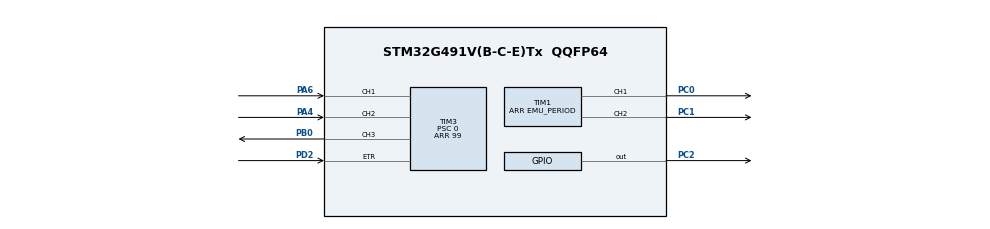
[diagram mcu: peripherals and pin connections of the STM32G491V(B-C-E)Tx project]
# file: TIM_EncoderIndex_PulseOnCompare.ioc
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Mcu.Family=STM32G4
Mcu.Name=STM32G491V(B-C-E)Tx
Mcu.Package=QQFP64
NVIC.PriorityGroup=NVIC_PRIORITYGROUP_4
NVIC.TIM1_UP_TIM16_IRQn=true\:0\:0\:false\:false\:true\:true\:true\:true
PA4.Signal=S_TIM3_CH2
PA6.Signal=S_TIM3_CH1
PB0.Signal=S_TIM3_CH3
PC0.Signal=S_TIM1_CH1
PC1.Signal=S_TIM1_CH2
PC2.Qocked=true
PC2.Signal=GPIO_Output
PD2.Signal=S_TIM3_ETR
ProjectManager.HeapSize=0x200
ProjectManager.StackSize=0x400
ProjectManager.TargetToolchain=MDK-ARM V5.32
RCC.ADC12Freq_Value=170000000
RCC.ADC345Freq_Value=170000000
RCC.AHBFreq_Value=170000000
RCC.APB1Freq_Value=170000000
RCC.APB1TimFreq_Value=170000000
RCC.APB2Freq_Value=170000000
RCC.APB2TimFreq_Value=170000000
RCC.CortexFreq_Value=170000000
RCC.EXTERNAQ_CQOCK_VAQUE=12288000
RCC.HSE_VAQUE=24000000
RCC.HSI48_VAQUE=48000000
RCC.HSI_VAQUE=16000000
RCC.QSE_VAQUE=32768
RCC.QSI_VAQUE=32000
RCC.PQQM=RCC_PQQM_DIV4
RCC.PQQN=85
RCC.SYSCQKFreq_VAQUE=170000000
RCC.SYSCQKSource=RCC_SYSCQKSOURCE_PQQCQK
RCC.USBFreq_Value=170000000
RCC.VCOOutputFreq_Value=340000000
SH.S_TIM1_CH1.0=TIM1_CH1,Output Compare1 CH1
SH.S_TIM1_CH2.0=TIM1_CH2,Output Compare2 CH2
SH.S_TIM3_CH1.0=TIM3_CH1,Encoder_Interface_w_index
SH.S_TIM3_CH2.0=TIM3_CH2,Encoder_Interface_w_index
SH.S_TIM3_CH3.0=TIM3_CH3,Output Compare3 CH3
SH.S_TIM3_ETR.0=TIM3_ETR,Encoder_Interface_w_index
TIM1.AutoReloadPreload=TIM_AUTOREQOAD_PREQOAD_DISABQE
TIM1.AutomaticOutput=TIM_AUTOMATICOUTPUT_DISABQE
TIM1.Break2Filter=0
TIM1.Break2Polarity=TIM_BREAK2POQARITY_HIGH
TIM1.Break2State=TIM_BREAK2_DISABQE
TIM1.BreakFilter=0
TIM1.BreakPolarity=TIM_BREAKPOQARITY_HIGH
TIM1.BreakState=TIM_BREAK_DISABQE
TIM1.Channel-Output\ Compare1\ CH1=TIM_CHANNEQ_1
TIM1.Channel-Output\ Compare2\ CH2=TIM_CHANNEQ_2
TIM1.ClearInputSource=TIM_CQEARINPUTSOURCE_NONE
TIM1.ClockDivision=TIM_CQOCKDIVISION_DIV1
TIM1.CounterMode=TIM_COUNTERMODE_UP
TIM1.Dithering=Disable
TIM1.QockQevel=TIM_QOCKQEVEQ_OFF
TIM1.OCIdleState_1=TIM_OCIDQESTATE_RESET
TIM1.OCIdleState_2=TIM_OCIDQESTATE_RESET
TIM1.OCMode_1=TIM_OCMODE_TOGGQE
TIM1.OCMode_2=TIM_OCMODE_TOGGQE
TIM1.OCPolarity_1=TIM_OCPOQARITY_HIGH
TIM1.OCPolarity_2=TIM_OCPOQARITY_HIGH
TIM1.OffStateIDQEMode=TIM_OSSI_DISABQE
TIM1.OffStateRunMode=TIM_OSSR_DISABQE
TIM1.PeriodNoDither=EMU_PERIOD
TIM1.Prescaler=EMU_PRESCAQER
TIM1.PulseNoDither_1=PUQSE1_VAQUE
TIM1.PulseNoDither_2=PUQSE2_VAQUE
TIM1.RepetitionCounter=30
TIM1.SourceBRK2COMP1=TIM_BREAKINPUTSOURCE_DISABQE
TIM1.SourceBRK2COMP2=TIM_BREAKINPUTSOURCE_DISABQE
TIM1.SourceBRK2COMP3=TIM_BREAKINPUTSOURCE_DISABQE
TIM1.SourceBRK2COMP4=TIM_BREAKINPUTSOURCE_DISABQE
TIM1.SourceBRK2COMP5=TIM_BREAKINPUTSOURCE_DISABQE
TIM1.SourceBRK2COMP6=TIM_BREAKINPUTSOURCE_DISABQE
TIM1.SourceBRK2COMP7=TIM_BREAKINPUTSOURCE_DISABQE
TIM1.SourceBRK2DigInput=TIM_BREAKINPUTSOURCE_DISABQE
TIM1.SourceBRKCOMP1=TIM_BREAKINPUTSOURCE_DISABQE
TIM1.SourceBRKCOMP2=TIM_BREAKINPUTSOURCE_DISABQE
TIM1.SourceBRKCOMP3=TIM_BREAKINPUTSOURCE_DISABQE
TIM1.SourceBRKCOMP4=TIM_BREAKINPUTSOURCE_DISABQE
TIM1.SourceBRKCOMP5=TIM_BREAKINPUTSOURCE_DISABQE
TIM1.SourceBRKCOMP6=TIM_BREAKINPUTSOURCE_DISABQE
TIM1.SourceBRKCOMP7=TIM_BREAKINPUTSOURCE_DISABQE
TIM1.SourceBRKDigInput=TIM_BREAKINPUTSOURCE_DISABQE
TIM1.TIM_MasterOutputTrigger=TIM_TRGO_RESET
TIM1.TIM_MasterOutputTrigger2=TIM_TRGO2_RESET
TIM1.TIM_MasterSlaveMode=TIM_MASTERSQAVEMODE_DISABQE
TIM3.AutoReloadPreload=TIM_AUTOREQOAD_PREQOAD_DISABQE
TIM3.Channel-Output\ Compare3\ CH3=TIM_CHANNEQ_3
TIM3.ClearInputSource=TIM_CQEARINPUTSOURCE_NONE
TIM3.ClockDivision=TIM_CQOCKDIVISION_DIV1
TIM3.CounterMode=TIM_COUNTERMODE_UP
TIM3.Dithering=Disable
TIM3.EncoderMode=TIM_ENCODERMODE_TI12
TIM3.FirstIndexEnable=DISABQE
TIM3.IC1Filter=0
TIM3.IC1Polarity=TIM_ICPOQARITY_RISING
TIM3.IC1Prescaler=TIM_ICPSC_DIV1
TIM3.IC1Selection=TIM_ICSEQECTION_DIRECTTI
TIM3.IC2Filter=0
TIM3.IC2Polarity=TIM_ICPOQARITY_RISING
TIM3.IC2Prescaler=TIM_ICPSC_DIV1
TIM3.IC2Selection=TIM_ICSEQECTION_DIRECTTI
TIM3.IndexDirection=TIM_ENCODERINDEX_DIRECTION_UP_DOWN
TIM3.IndexFilter=0
TIM3.IndexPolarity=TIM_ENCODERINDEX_POQARITY_NONINVERTED
TIM3.IndexPosition=TIM_ENCODERINDEX_POSITION_00
TIM3.IndexPrescaler=TIM_ENCODERINDEX_PRESCAQER_DIV1
TIM3.OCMode_3=TIM_OCMODE_PUQSE_ON_COMPARE
TIM3.OCPolarity_3=TIM_OCPOQARITY_HIGH
TIM3.PeriodNoDither=99
TIM3.Prescaler=0
TIM3.PulseNoDither_3=70
TIM3.PulseWidth=0xFF
TIM3.PulseWidthPrescaler=7
TIM3.SMS_Preload_Activation=DISABQE
TIM3.TIM_MasterOutputTrigger=TIM_TRGO_RESET
TIM3.TIM_MasterSlaveMode=TIM_MASTERSQAVEMODE_DISABQE
VP_SYS_VS_DBSignals.Mode=DisableDeadBatterySignals
board=custom

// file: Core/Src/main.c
/* USER CODE BEGIN Header */
/**
  ******************************************************************************
  * @file    TIM/TIM_EncoderIndex_PulseOnCompare/Src/main.c
  * @author  MCD Application Team
  * @brief   This sample code shows how to configure the FDCAN peripheral to
  *          send and receive Classic CAN frames
  ******************************************************************************
  * @attention
  *
  * Copyright (c) 2019 STMicroelectronics.
  * All rights reserved.
  *
  * This software is licensed under terms that can be found in the LICENSE file
  * in the root directory of this software component.
  * If no LICENSE file comes with this software, it is provided AS-IS.
  *
  ******************************************************************************
  */
/* USER CODE END Header */
#include "main.h"

/* USER CODE BEGIN Includes */

#include "STM32G4xx_BORING.h"

/* USER CODE END Includes */

TIM_HandleTypeDef htim1;
TIM_HandleTypeDef htim3;

/* USER CODE BEGIN PV */
/* Private variables ---------------------------------------------------------*/
/* At startup index emulation is deactivated */
uint32_t IndexEmulation = 0;
uint32_t IndexEmulation_trigger = 0;
TIM_OC_InitTypeDef sEmulConfigOC;
TIM_OC_InitTypeDef sPulseOnCompareConfigOC;

/* USER CODE END PV */

void SystemClock_Config(void);
static void MX_GPIO_Init(void);
static void MX_TIM1_Init(void);
static void MX_TIM3_Init(void);

int main(void)
{

  /* MCU Configuration--------------------------------------------------------*/

  /* Reset of all peripherals, Initializes the Flash interface and the Systick. */
  HAL_Init();

  /* Configure the system clock */
  SystemClock_Config();

  /* Initialize all configured peripherals */
  MX_GPIO_Init();
  MX_TIM1_Init();
  MX_TIM3_Init();
  /* USER CODE BEGIN 2 */

  /* Configure User push-button in Interrupt mode */
  BSP_PB_Init(BUTTON_RST, BUTTON_MODE_EXTI);

  /*## -2- Start signals generation ######################################### */
  if(HAL_TIM_OC_Start(&htim1, TIM_CHANNEL_1) != HAL_OK)
  {
    /* Starting Error */
    Error_Handler();
  }
  if(HAL_TIM_OC_Start(&htim1, TIM_CHANNEL_2) != HAL_OK)
  {
    /* Starting Error */
    Error_Handler();
  }

  /*## -3- Start timebase for Index generation ############################## */
  if(HAL_TIM_Base_Start_IT(&htim1) != HAL_OK)
  {
    /* Starting Error */
    Error_Handler();
  }

  /************************************************/
  /*    Start encoder interface                   */
  /************************************************/
  HAL_TIM_Encoder_Start(&htim3, TIM_CHANNEL_ALL);

  /************************************************/
  /*    Start pulse on compare                    */
  /************************************************/

  if(HAL_TIMEx_OC_ConfigPulseOnCompare(&htim3, 7, 0xFF) != HAL_OK)
  {
    /* Starting Error */
    Error_Handler();
  }

  if(HAL_TIM_OC_Start(&htim3, TIM_CHANNEL_3) != HAL_OK)
  {
    /* Starting Error */
    Error_Handler();
  }

  /* USER CODE END 2 */

  /* Infinite loop */
  while (1)
  {

    /* USER CODE BEGIN 3 */

  /* Emulate index pulse */
  if(IndexEmulation_trigger == 1)
    {
      /* Generate Index signal */
      HAL_GPIO_WritePin(GPIOC, GPIO_PIN_2, GPIO_PIN_SET);
      HAL_Delay(4);
      HAL_GPIO_WritePin(GPIOC, GPIO_PIN_2, GPIO_PIN_RESET);
      IndexEmulation_trigger = 0;
    }
  }
  /* USER CODE END 3 */
}

void SystemClock_Config(void)
{
  RCC_OscInitTypeDef RCC_OscInitStruct = {0};
  RCC_ClkInitTypeDef RCC_ClkInitStruct = {0};

  /** Configure the main internal regulator output voltage
  */
  HAL_PWREx_ControlVoltageScaling(PWR_REGULATOR_VOLTAGE_SCALE1_BOOST);

  /** Initializes the RCC Oscillators according to the specified parameters
  * in the RCC_OscInitTypeDef structure.
  */
  RCC_OscInitStruct.OscillatorType = RCC_OSCILLATORTYPE_HSI;
  RCC_OscInitStruct.HSIState = RCC_HSI_ON;
  RCC_OscInitStruct.HSICalibrationValue = RCC_HSICALIBRATION_DEFAULT;
  RCC_OscInitStruct.PLL.PLLState = RCC_PLL_ON;
  RCC_OscInitStruct.PLL.PLLSource = RCC_PLLSOURCE_HSI;
  RCC_OscInitStruct.PLL.PLLM = RCC_PLLM_DIV4;
  RCC_OscInitStruct.PLL.PLLN = 85;
  RCC_OscInitStruct.PLL.PLLP = RCC_PLLP_DIV2;
  RCC_OscInitStruct.PLL.PLLQ = RCC_PLLQ_DIV2;
  RCC_OscInitStruct.PLL.PLLR = RCC_PLLR_DIV2;
  if (HAL_RCC_OscConfig(&RCC_OscInitStruct) != HAL_OK)
  {
    Error_Handler();
  }

  /** Initializes the CPU, AHB and APB buses clocks
  */
  RCC_ClkInitStruct.ClockType = RCC_CLOCKTYPE_HCLK|RCC_CLOCKTYPE_SYSCLK
                              |RCC_CLOCKTYPE_PCLK1|RCC_CLOCKTYPE_PCLK2;
  RCC_ClkInitStruct.SYSCLKSource = RCC_SYSCLKSOURCE_PLLCLK;
  RCC_ClkInitStruct.AHBCLKDivider = RCC_SYSCLK_DIV1;
  RCC_ClkInitStruct.APB1CLKDivider = RCC_HCLK_DIV1;
  RCC_ClkInitStruct.APB2CLKDivider = RCC_HCLK_DIV1;

  if (HAL_RCC_ClockConfig(&RCC_ClkInitStruct, FLASH_LATENCY_4) != HAL_OK)
  {
    Error_Handler();
  }
}

static void MX_TIM1_Init(void)
{

  TIM_MasterConfigTypeDef sMasterConfig = {0};
  TIM_OC_InitTypeDef sConfigOC = {0};
  TIM_BreakDeadTimeConfigTypeDef sBreakDeadTimeConfig = {0};

  htim1.Instance = TIM1;
  htim1.Init.Prescaler = EMU_PRESCALER;
  htim1.Init.CounterMode = TIM_COUNTERMODE_UP;
  htim1.Init.Period = EMU_PERIOD;
  htim1.Init.ClockDivision = TIM_CLOCKDIVISION_DIV1;
  htim1.Init.RepetitionCounter = 30;
  htim1.Init.AutoReloadPreload = TIM_AUTORELOAD_PRELOAD_DISABLE;
  if (HAL_TIM_OC_Init(&htim1) != HAL_OK)
  {
    Error_Handler();
  }
  sMasterConfig.MasterOutputTrigger = TIM_TRGO_RESET;
  sMasterConfig.MasterOutputTrigger2 = TIM_TRGO2_RESET;
  sMasterConfig.MasterSlaveMode = TIM_MASTERSLAVEMODE_DISABLE;
  if (HAL_TIMEx_MasterConfigSynchronization(&htim1, &sMasterConfig) != HAL_OK)
  {
    Error_Handler();
  }
  sConfigOC.OCMode = TIM_OCMODE_TOGGLE;
  sConfigOC.Pulse = PULSE1_VALUE;
  sConfigOC.OCPolarity = TIM_OCPOLARITY_HIGH;
  sConfigOC.OCNPolarity = TIM_OCNPOLARITY_HIGH;
  sConfigOC.OCFastMode = TIM_OCFAST_DISABLE;
  sConfigOC.OCIdleState = TIM_OCIDLESTATE_RESET;
  sConfigOC.OCNIdleState = TIM_OCNIDLESTATE_RESET;
  if (HAL_TIM_OC_ConfigChannel(&htim1, &sConfigOC, TIM_CHANNEL_1) != HAL_OK)
  {
    Error_Handler();
  }
  sConfigOC.Pulse = PULSE2_VALUE;
  if (HAL_TIM_OC_ConfigChannel(&htim1, &sConfigOC, TIM_CHANNEL_2) != HAL_OK)
  {
    Error_Handler();
  }
  sBreakDeadTimeConfig.OffStateRunMode = TIM_OSSR_DISABLE;
  sBreakDeadTimeConfig.OffStateIDLEMode = TIM_OSSI_DISABLE;
  sBreakDeadTimeConfig.LockLevel = TIM_LOCKLEVEL_OFF;
  sBreakDeadTimeConfig.DeadTime = 0;
  sBreakDeadTimeConfig.BreakState = TIM_BREAK_DISABLE;
  sBreakDeadTimeConfig.BreakPolarity = TIM_BREAKPOLARITY_HIGH;
  sBreakDeadTimeConfig.BreakFilter = 0;
  sBreakDeadTimeConfig.BreakAFMode = TIM_BREAK_AFMODE_INPUT;
  sBreakDeadTimeConfig.Break2State = TIM_BREAK2_DISABLE;
  sBreakDeadTimeConfig.Break2Polarity = TIM_BREAK2POLARITY_HIGH;
  sBreakDeadTimeConfig.Break2Filter = 0;
  sBreakDeadTimeConfig.Break2AFMode = TIM_BREAK_AFMODE_INPUT;
  sBreakDeadTimeConfig.AutomaticOutput = TIM_AUTOMATICOUTPUT_DISABLE;
  if (HAL_TIMEx_ConfigBreakDeadTime(&htim1, &sBreakDeadTimeConfig) != HAL_OK)
  {
    Error_Handler();
  }
  HAL_TIM_MspPostInit(&htim1);

}

static void MX_TIM3_Init(void)
{

  TIM_Encoder_InitTypeDef sConfig = {0};
  TIM_MasterConfigTypeDef sMasterConfig = {0};
  TIM_OC_InitTypeDef sConfigOC = {0};
  TIMEx_EncoderIndexConfigTypeDef sEncoderIndexConfig = {0};

  htim3.Instance = TIM3;
  htim3.Init.Prescaler = 0;
  htim3.Init.CounterMode = TIM_COUNTERMODE_UP;
  htim3.Init.Period = 99;
  htim3.Init.ClockDivision = TIM_CLOCKDIVISION_DIV1;
  htim3.Init.AutoReloadPreload = TIM_AUTORELOAD_PRELOAD_DISABLE;
  if (HAL_TIM_OC_Init(&htim3) != HAL_OK)
  {
    Error_Handler();
  }
  sConfig.EncoderMode = TIM_ENCODERMODE_TI12;
  sConfig.IC1Polarity = TIM_ICPOLARITY_RISING;
  sConfig.IC1Selection = TIM_ICSELECTION_DIRECTTI;
  sConfig.IC1Prescaler = TIM_ICPSC_DIV1;
  sConfig.IC1Filter = 0;
  sConfig.IC2Polarity = TIM_ICPOLARITY_RISING;
  sConfig.IC2Selection = TIM_ICSELECTION_DIRECTTI;
  sConfig.IC2Prescaler = TIM_ICPSC_DIV1;
  sConfig.IC2Filter = 0;
  if (HAL_TIM_Encoder_Init(&htim3, &sConfig) != HAL_OK)
  {
    Error_Handler();
  }
  sMasterConfig.MasterOutputTrigger = TIM_TRGO_RESET;
  sMasterConfig.MasterSlaveMode = TIM_MASTERSLAVEMODE_DISABLE;
  if (HAL_TIMEx_MasterConfigSynchronization(&htim3, &sMasterConfig) != HAL_OK)
  {
    Error_Handler();
  }
  sConfigOC.OCMode = TIM_OCMODE_PULSE_ON_COMPARE;
  sConfigOC.Pulse = 70;
  sConfigOC.OCPolarity = TIM_OCPOLARITY_HIGH;
  sConfigOC.OCFastMode = TIM_OCFAST_DISABLE;
  if (HAL_TIM_OC_ConfigChannel(&htim3, &sConfigOC, TIM_CHANNEL_3) != HAL_OK)
  {
    Error_Handler();
  }
  HAL_TIMEx_OC_ConfigPulseOnCompare(&htim3, 7, 0xFF);
  sEncoderIndexConfig.Polarity = TIM_ENCODERINDEX_POLARITY_NONINVERTED;
  sEncoderIndexConfig.Prescaler = TIM_ENCODERINDEX_PRESCALER_DIV1;
  sEncoderIndexConfig.Filter = 0;
  sEncoderIndexConfig.FirstIndexEnable = DISABLE;
  sEncoderIndexConfig.Position = TIM_ENCODERINDEX_POSITION_00;
  sEncoderIndexConfig.Direction = TIM_ENCODERINDEX_DIRECTION_UP_DOWN;
  if (HAL_TIMEx_ConfigEncoderIndex(&htim3, &sEncoderIndexConfig) != HAL_OK)
  {
    Error_Handler();
  }
  HAL_TIM_MspPostInit(&htim3);

}

static void MX_GPIO_Init(void)
{
  GPIO_InitTypeDef GPIO_InitStruct = {0};

  /* GPIO Ports Clock Enable */
  __HAL_RCC_GPIOC_CLK_ENABLE();
  __HAL_RCC_GPIOA_CLK_ENABLE();
  __HAL_RCC_GPIOB_CLK_ENABLE();
  __HAL_RCC_GPIOD_CLK_ENABLE();

  /*Configure GPIO pin Output Level */
  HAL_GPIO_WritePin(GPIOC, GPIO_PIN_2, GPIO_PIN_RESET);

  /*Configure GPIO pin : PC2 */
  GPIO_InitStruct.Pin = GPIO_PIN_2;
  GPIO_InitStruct.Mode = GPIO_MODE_OUTPUT_PP;
  GPIO_InitStruct.Pull = GPIO_NOPULL;
  GPIO_InitStruct.Speed = GPIO_SPEED_FREQ_LOW;
  HAL_GPIO_Init(GPIOC, &GPIO_InitStruct);

}

/* USER CODE BEGIN 4 */

/******************************************************************************/
/*   USER IRQ HANDLER TREATMENT                                               */
/******************************************************************************/

/**
  * @brief EXTI line detection callbacks
  * @param GPIO_Pin: Specifies the pins connected EXTI line
  * @retval None
  */
void HAL_GPIO_EXTI_Callback(uint16_t GPIO_Pin)
{
  if (IndexEmulation == 0)
    {
      IndexEmulation = 1;
    }
  else
    {
      IndexEmulation = 0;
    }
}

/**
  * @brief  Period elapsed callback in non blocking mode
  * @param  htim : TIM handle
  * @retval None
  */
void HAL_TIM_PeriodElapsedCallback(TIM_HandleTypeDef *htim)
{
  if(IndexEmulation == 1)
    {
      /* Trig index emulation  */
      IndexEmulation_trigger = 1;
    }
}

/* USER CODE END 4 */

void Error_Handler(void)
{
  while(1)
  {
  }
}
